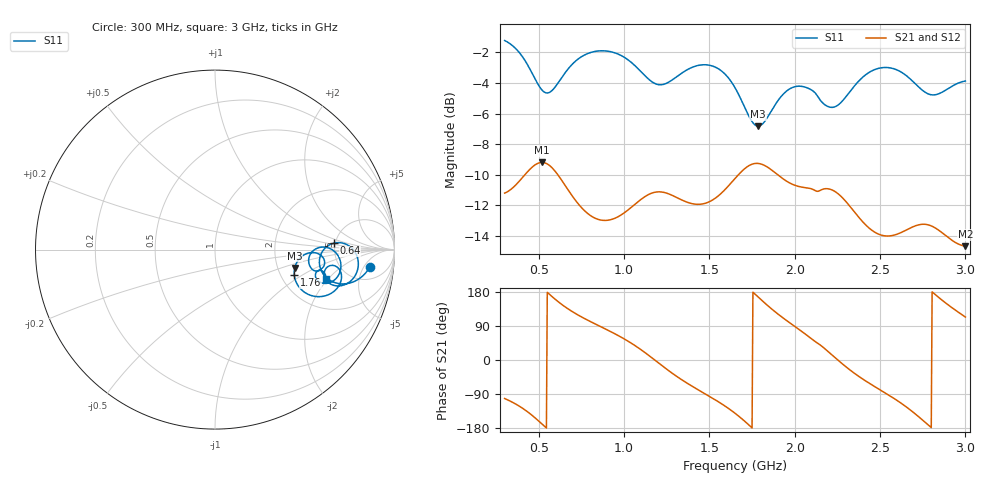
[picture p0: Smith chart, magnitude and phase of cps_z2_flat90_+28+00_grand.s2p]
! cps_z2_flat90_+28+00_grand
! simulated by sim/fixtures_fdtd.py (S12 = S21, S22 not computed)
# HZ S RI R 50
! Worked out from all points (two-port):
!   541 points, 300 MHz to 3 GHz, reference 50 ohm
!   highest |S21| = -9.20 dB at 520 MHz (marker M1); lowest = -14.7 dB at 3 GHz (marker M2)
!   |S21| within 3 dB of the highest: start of sweep to 754.6 MHz; 1.035 GHz to 2.333 GHz (1.298 GHz wide, 77.1 % of centre)
!   lowest |S11| = -6.8 dB at 1.785 GHz (marker M3), VSWR 2.67, Z = 124 - j32.2 ohm
!   |S11| at or under -10 dB: nowhere
!   |S22| runs from - to - dB; largest |S21 - S12| = 0
!   S11 on the Smith chart (normalised r, x): 300 MHz: 9, -7; 640 MHz: 4.85, +0.62; 1.76 GHz: 2.36, -0.86; 3 GHz: 3.41, -1.91
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3e8  0.8627 -0.097  -0.0552 -0.2698  -0.0552 -0.2698  0 0
4.25e8  0.7128 -0.1913  -0.2197 -0.2313  -0.2197 -0.2313  0 0
5.2e8  0.5876 -0.1062  -0.3408 -0.0648  -0.3408 -0.0648  0 0
6.4e8  0.6622 0.0359  -0.2455 0.1727  -0.2455 0.1727  0 0
7.5e8  0.7681 0.00211  -0.0997 0.2261  -0.0997 0.2261  0 0
8.85e8  0.7959 -0.106  0.0269 0.2226  0.0269 0.2226  0 0
1.025e9  0.7232 -0.1953  0.1588 0.184  0.1588 0.184  0 0
1.2e9  0.6083 -0.1342  0.2759 -0.0345  0.2759 -0.0345  0 0
1.4e9  0.6992 -0.1216  0.0888 -0.2383  0.0888 -0.2383  0 0
1.525e9  0.681 -0.2147  -0.0572 -0.2566  -0.0572 -0.2566  0 0
1.65e9  0.5504 -0.2596  -0.2371 -0.1955  -0.2371 -0.1955  0 0
1.76e9  0.4417 -0.1424  -0.3431 0.019  -0.3431 0.019  0 0
1.785e9  0.4439 -0.1029  -0.3347 0.0808  -0.3347 0.0808  0 0
1.92e9  0.5689 -0.0204  -0.1306 0.2811  -0.1306 0.2811  0 0
2.1e9  0.5869 -0.112  0.1614 0.2339  0.1614 0.2339  0 0
2.26e9  0.5372 -0.0166  0.272 -0.014  0.272 -0.014  0 0
2.38e9  0.6439 0.00445  0.1621 -0.1604  0.1621 -0.1604  0 0
2.55e9  0.697 -0.1219  -0.00823 -0.1993  -0.00823 -0.1993  0 0
2.67e9  0.6276 -0.1875  -0.1336 -0.1632  -0.1336 -0.1632  0 0
2.78e9  0.5608 -0.1538  -0.2141 -0.0357  -0.2141 -0.0357  0 0
2.885e9  0.5865 -0.1156  -0.1736 0.0993  -0.1736 0.0993  0 0
3e9  0.6182 -0.1652  -0.0733 0.1696  -0.0733 0.1696  0 0
